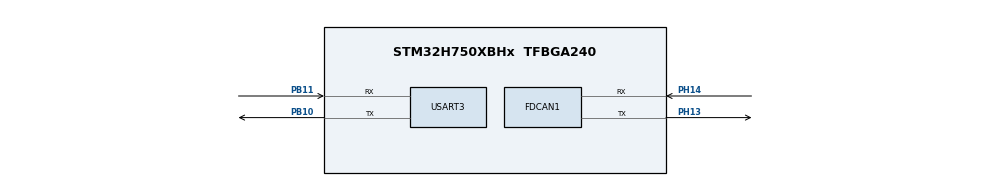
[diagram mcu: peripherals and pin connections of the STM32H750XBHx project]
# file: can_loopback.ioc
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FDCAN1.CalculateBaudRateNominal=500000
FDCAN1.CalculateTimeBitNominal=2000
FDCAN1.CalculateTimeQuantumNominal=200.0
FDCAN1.DataSyncJumpWidth=2
FDCAN1.DataTimeSeg1=7
FDCAN1.DataTimeSeg2=2
FDCAN1.Mode=FDCAN_MODE_INTERNAL_LOOPBACK
FDCAN1.NominalPrescaler=5
FDCAN1.NominalTimeSeg1=7
FDCAN1.RxFifo0ElmtsNbr=8
FDCAN1.StdFiltersNbr=1
FDCAN1.TxFifoQueueElmtsNbr=8
Mcu.Family=STM32H7
Mcu.Name=STM32H750XBHx
Mcu.Package=TFBGA240
NVIC.FDCAN1_IT0_IRQn=true\:0\:0\:false\:false\:true\:true\:true\:true
NVIC.PriorityGroup=NVIC_PRIORITYGROUP_4
PA13\ (JTMS/SWDIO).Mode=Serial_Wire
PA13\ (JTMS/SWDIO).Signal=DEBUG_JTMS-SWDIO
PA14\ (JTCK/SWCLK).Mode=Serial_Wire
PA14\ (JTCK/SWCLK).Signal=DEBUG_JTCK-SWCLK
PB10.Mode=Asynchronous
PB10.Signal=USART3_TX
PB11.Mode=Asynchronous
PB11.Signal=USART3_RX
PC14-OSC32_IN\ (OSC32_IN).Mode=LSE-External-Clock-Source
PC14-OSC32_IN\ (OSC32_IN).Signal=RCC_OSC32_IN
PH0-OSC_IN\ (PH0).Mode=HSE-External-Clock-Source
PH0-OSC_IN\ (PH0).Signal=RCC_OSC_IN
PH13.Mode=FDCAN_Activate
PH13.Signal=FDCAN1_TX
PH14.Mode=FDCAN_Activate
PH14.Signal=FDCAN1_RX
ProjectManager.HeapSize=0x200
ProjectManager.StackSize=0x400
ProjectManager.TargetToolchain=STM32CubeIDE
RCC.ADCFreq_Value=129000000
RCC.APB1Freq_Value=25000000
RCC.APB2Freq_Value=25000000
RCC.APB3Freq_Value=25000000
RCC.APB4Freq_Value=25000000
RCC.CortexFreq_Value=25000000
RCC.FDCANCLockSelection=RCC_FDCANCLKSOURCE_HSE
RCC.HCLKFreq_Value=25000000
RCC.SYSCLKFreq_VALUE=25000000
RCC.SYSCLKSource=RCC_SYSCLKSOURCE_HSE
RCC.USBFreq_Value=129000000
USART3.VirtualMode-Asynchronous=VM_ASYNC
board=custom

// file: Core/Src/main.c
/* USER CODE BEGIN Header */
/**
  ******************************************************************************
  * @file           : main.c
  * @brief          : Main program body
  ******************************************************************************
  * @attention
  *
  * Copyright (c) 2026 STMicroelectronics.
  * All rights reserved.
  *
  * This software is licensed under terms that can be found in the LICENSE file
  * in the root directory of this software component.
  * If no LICENSE file comes with this software, it is provided AS-IS.
  *
  ******************************************************************************
  */
/* USER CODE END Header */
#include "main.h"

/* USER CODE BEGIN Includes */
#include "can_app.h"   // CAN 測試流程 (Core/Src/can_app.c)，參數在 can_config.h
/* USER CODE END Includes */

FDCAN_HandleTypeDef hfdcan1;

UART_HandleTypeDef huart3;

void SystemClock_Config(void);
static void MPU_Config(void);
static void MX_GPIO_Init(void);
static void MX_FDCAN1_Init(void);
static void MX_USART3_UART_Init(void);

/* USER CODE BEGIN 0 */
int __io_putchar(int ch)   // 讓 printf 輸出到 USART3
{
  HAL_UART_Transmit(&huart3, (uint8_t *)&ch, 1, HAL_MAX_DELAY);
  return ch;
}
/* USER CODE END 0 */

int main(void)
{

  /* MPU Configuration--------------------------------------------------------*/
  MPU_Config();

  /* MCU Configuration--------------------------------------------------------*/

  /* Reset of all peripherals, Initializes the Flash interface and the Systick. */
  HAL_Init();

  /* USER CODE BEGIN Init */
  SCB_EnableICache();   // 指令快取：400 MHz 下 Flash 有等待週期，靠 I-Cache 補回執行速度
                        // D-Cache 不開：LCD 畫面緩衝區由 DMA2D / LTDC 直接存取，開了要處理快取一致性
  /* USER CODE END Init */

  /* Configure the system clock */
  SystemClock_Config();

  /* Initialize all configured peripherals */
  MX_GPIO_Init();
  MX_FDCAN1_Init();
  MX_USART3_UART_Init();
  /* USER CODE BEGIN 2 */
  CAN_App_Init(&hfdcan1);   // 啟動 FDCAN 收發、延遲量測、比對和 LCD
  /* USER CODE END 2 */

  /* Infinite loop */
  while (1)
  {

    /* USER CODE BEGIN 3 */
    CAN_App_Process();      // 時間到就送一包，有收到就比對、量測並顯示
  }
  /* USER CODE END 3 */
}

void SystemClock_Config(void)
{
  RCC_OscInitTypeDef RCC_OscInitStruct = {0};
  RCC_ClkInitTypeDef RCC_ClkInitStruct = {0};

  /** Supply configuration update enable
  */
  HAL_PWREx_ConfigSupply(PWR_LDO_SUPPLY);

  /** Configure the main internal regulator output voltage
  */
  __HAL_PWR_VOLTAGESCALING_CONFIG(PWR_REGULATOR_VOLTAGE_SCALE1);   // 400 MHz 需要 VOS1

  while(!__HAL_PWR_GET_FLAG(PWR_FLAG_VOSRDY)) {}

  /** Initializes the RCC Oscillators according to the specified parameters
  * in the RCC_OscInitTypeDef structure.
  */
  RCC_OscInitStruct.OscillatorType = RCC_OSCILLATORTYPE_HSE;
  RCC_OscInitStruct.HSEState = RCC_HSE_BYPASS;
  RCC_OscInitStruct.PLL.PLLState = RCC_PLL_ON;
  RCC_OscInitStruct.PLL.PLLSource = RCC_PLLSOURCE_HSE;   // 三組 PLL 共用來源，LTDC 的 PLL3 也要 HSE
  RCC_OscInitStruct.PLL.PLLM = 5;                        // 25 MHz / 5 = 5 MHz
  RCC_OscInitStruct.PLL.PLLN = 160;                      // x 160 = 800 MHz (VCO)
  RCC_OscInitStruct.PLL.PLLP = 2;                        // / 2 = 400 MHz -> SYSCLK
  RCC_OscInitStruct.PLL.PLLQ = 4;
  RCC_OscInitStruct.PLL.PLLR = 2;
  RCC_OscInitStruct.PLL.PLLRGE = RCC_PLL1VCIRANGE_2;     // PLL 輸入 4~8 MHz
  RCC_OscInitStruct.PLL.PLLVCOSEL = RCC_PLL1VCOWIDE;
  RCC_OscInitStruct.PLL.PLLFRACN = 0;
  if (HAL_RCC_OscConfig(&RCC_OscInitStruct) != HAL_OK)
  {
    Error_Handler();
  }

  /** Initializes the CPU, AHB and APB buses clocks
  */
  RCC_ClkInitStruct.ClockType = RCC_CLOCKTYPE_HCLK|RCC_CLOCKTYPE_SYSCLK
                              |RCC_CLOCKTYPE_PCLK1|RCC_CLOCKTYPE_PCLK2
                              |RCC_CLOCKTYPE_D3PCLK1|RCC_CLOCKTYPE_D1PCLK1;
  RCC_ClkInitStruct.SYSCLKSource = RCC_SYSCLKSOURCE_PLLCLK;
  RCC_ClkInitStruct.SYSCLKDivider = RCC_SYSCLK_DIV1;     // CPU 400 MHz
  RCC_ClkInitStruct.AHBCLKDivider = RCC_HCLK_DIV2;       // AXI / AHB 200 MHz
  RCC_ClkInitStruct.APB3CLKDivider = RCC_APB3_DIV2;      // 四組 APB 都是 100 MHz
  RCC_ClkInitStruct.APB1CLKDivider = RCC_APB1_DIV2;
  RCC_ClkInitStruct.APB2CLKDivider = RCC_APB2_DIV2;
  RCC_ClkInitStruct.APB4CLKDivider = RCC_APB4_DIV2;      // 要和 APB2 相同：BSP 用 PCLK2 計算 I2C4 (觸控 IC) 的時序

  if (HAL_RCC_ClockConfig(&RCC_ClkInitStruct, FLASH_LATENCY_4) != HAL_OK)   // 4 WS：保守設定，一定在規格內
  {
    Error_Handler();
  }
}

static void MX_FDCAN1_Init(void)
{

  hfdcan1.Instance = FDCAN1;
  hfdcan1.Init.FrameFormat = FDCAN_FRAME_FD_BRS;      // CAN FD，資料段切換到較高位元率 (BRS)
  hfdcan1.Init.Mode = FDCAN_MODE_INTERNAL_LOOPBACK;
  hfdcan1.Init.AutoRetransmission = DISABLE;
  hfdcan1.Init.TransmitPause = DISABLE;
  hfdcan1.Init.ProtocolException = DISABLE;
  hfdcan1.Init.NominalPrescaler = 1;     // 25 MHz / 1 = 25 MHz -> 1 tq = 40 ns
  hfdcan1.Init.NominalSyncJumpWidth = 1;
  hfdcan1.Init.NominalTimeSeg1 = 19;     // 1 + 19 + 5 = 25 tq = 1 us -> 1 Mbit/s
  hfdcan1.Init.NominalTimeSeg2 = 5;      // 取樣點 (1 + 19) / 25 = 80%
  hfdcan1.Init.DataPrescaler = 1;        // 資料段 (BRS 開啟時才使用)：1 tq = 40 ns
  hfdcan1.Init.DataSyncJumpWidth = 1;    // SJW 不能大於 Seg2
  hfdcan1.Init.DataTimeSeg1 = 3;         // 1 + 3 + 1 = 5 tq = 200 ns -> 5 Mbit/s
  hfdcan1.Init.DataTimeSeg2 = 1;         // 取樣點 (1 + 3) / 5 = 80%；每 bit 只有 5 tq，接實體匯流排前應提高 FDCAN 時脈
  hfdcan1.Init.MessageRAMOffset = 0;
  hfdcan1.Init.StdFiltersNbr = 0;
  hfdcan1.Init.ExtFiltersNbr = 1;                      // 改用 29-bit ID 的過濾器
  hfdcan1.Init.RxFifo0ElmtsNbr = 8;
  hfdcan1.Init.RxFifo0ElmtSize = FDCAN_DATA_BYTES_16;  // Message RAM 每格要放得下 CAN_APP_DATA_LEN (can_config.h)
  hfdcan1.Init.RxFifo1ElmtsNbr = 0;
  hfdcan1.Init.RxFifo1ElmtSize = FDCAN_DATA_BYTES_8;
  hfdcan1.Init.RxBuffersNbr = 0;
  hfdcan1.Init.RxBufferSize = FDCAN_DATA_BYTES_8;
  hfdcan1.Init.TxEventsNbr = 0;
  hfdcan1.Init.TxBuffersNbr = 0;
  hfdcan1.Init.TxFifoQueueElmtsNbr = 8;
  hfdcan1.Init.TxFifoQueueMode = FDCAN_TX_FIFO_OPERATION;
  hfdcan1.Init.TxElmtSize = FDCAN_DATA_BYTES_16;       // 同上
  if (HAL_FDCAN_Init(&hfdcan1) != HAL_OK)
  {
    Error_Handler();
  }

}

static void MX_USART3_UART_Init(void)
{

  huart3.Instance = USART3;
  huart3.Init.BaudRate = 115200;
  huart3.Init.WordLength = UART_WORDLENGTH_8B;
  huart3.Init.StopBits = UART_STOPBITS_1;
  huart3.Init.Parity = UART_PARITY_NONE;
  huart3.Init.Mode = UART_MODE_TX_RX;
  huart3.Init.HwFlowCtl = UART_HWCONTROL_NONE;
  huart3.Init.OverSampling = UART_OVERSAMPLING_16;
  huart3.Init.OneBitSampling = UART_ONE_BIT_SAMPLE_DISABLE;
  huart3.Init.ClockPrescaler = UART_PRESCALER_DIV1;
  huart3.AdvancedInit.AdvFeatureInit = UART_ADVFEATURE_NO_INIT;
  if (HAL_UART_Init(&huart3) != HAL_OK)
  {
    Error_Handler();
  }
  if (HAL_UARTEx_SetTxFifoThreshold(&huart3, UART_TXFIFO_THRESHOLD_1_8) != HAL_OK)
  {
    Error_Handler();
  }
  if (HAL_UARTEx_SetRxFifoThreshold(&huart3, UART_RXFIFO_THRESHOLD_1_8) != HAL_OK)
  {
    Error_Handler();
  }
  if (HAL_UARTEx_DisableFifoMode(&huart3) != HAL_OK)
  {
    Error_Handler();
  }

}

static void MX_GPIO_Init(void)
{

  /* GPIO Ports Clock Enable */
  __HAL_RCC_GPIOA_CLK_ENABLE();
  __HAL_RCC_GPIOH_CLK_ENABLE();
  __HAL_RCC_GPIOC_CLK_ENABLE();
  __HAL_RCC_GPIOB_CLK_ENABLE();

}

/* MPU Configuration */

void MPU_Config(void)
{
  MPU_Region_InitTypeDef MPU_InitStruct = {0};

  /* Disables the MPU */
  HAL_MPU_Disable();

  /** Initializes and configures the Region and the memory to be protected
  */
  MPU_InitStruct.Enable = MPU_REGION_ENABLE;
  MPU_InitStruct.Number = MPU_REGION_NUMBER0;
  MPU_InitStruct.BaseAddress = 0x0;
  MPU_InitStruct.Size = MPU_REGION_SIZE_4GB;
  MPU_InitStruct.SubRegionDisable = 0x87;
  MPU_InitStruct.TypeExtField = MPU_TEX_LEVEL0;
  MPU_InitStruct.AccessPermission = MPU_REGION_NO_ACCESS;
  MPU_InitStruct.DisableExec = MPU_INSTRUCTION_ACCESS_DISABLE;
  MPU_InitStruct.IsShareable = MPU_ACCESS_SHAREABLE;
  MPU_InitStruct.IsCacheable = MPU_ACCESS_NOT_CACHEABLE;
  MPU_InitStruct.IsBufferable = MPU_ACCESS_NOT_BUFFERABLE;

  HAL_MPU_ConfigRegion(&MPU_InitStruct);
  /* Enables the MPU */
  HAL_MPU_Enable(MPU_PRIVILEGED_DEFAULT);

}

void Error_Handler(void)
{
  __disable_irq();
  while (1)
  {
  }
}
